VERSION 5.8 ;
BUSBITCHARS "[]" ;
DIVIDERCHAR "/" ;

UNITS
  DATABASE MICRONS 1000 ;
END UNITS

MANUFACTURINGGRID 0.005 ;

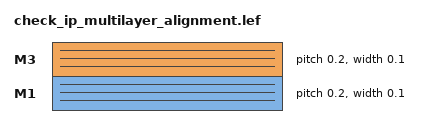
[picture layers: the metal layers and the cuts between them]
LAYER M1
  TYPE ROUTING ;
  DIRECTION HORIZONTAL ;
  PITCH 0.200 ;
  WIDTH 0.100 ;
END M1

LAYER M3
  TYPE ROUTING ;
  DIRECTION HORIZONTAL ;
  PITCH 0.200 ;
  WIDTH 0.100 ;
END M3

SITE unit
  CLASS CORE ;
  SIZE 0.200 BY 2.000 ;
  SYMMETRY Y ;
END unit

# M1 center_y=150: with track origin 100 it needs translation 150 mod 200.
# M3 center_y=50: with track origin 0 it also needs translation 150 mod 200.
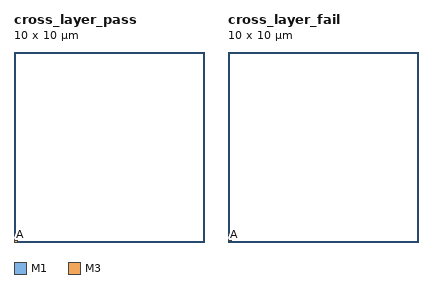
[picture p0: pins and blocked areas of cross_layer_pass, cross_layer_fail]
MACRO cross_layer_pass
  CLASS BLOCK ;
  ORIGIN 0 0 ;
  SIZE 10.000 BY 10.000 ;
  PIN A
    DIRECTION INPUT ;
    USE SIGNAL ;
    ANTENNAMODEL OXIDE1 ;
    PORT
      LAYER M1 ;
      RECT 0.000 0.100 0.200 0.200 ;
    END
  END A
  PIN B
    DIRECTION INPUT ;
    USE SIGNAL ;
    ANTENNAMODEL OXIDE1 ;
    PORT
      LAYER M3 ;
      RECT 0.000 0.000 0.200 0.100 ;
    END
  END B
END cross_layer_pass

# Both centers are 150. M1 needs translation 150 mod 200, while M3 needs
# translation 50 mod 200. Each layer can align alone, but not simultaneously.
MACRO cross_layer_fail
  CLASS BLOCK ;
  ORIGIN 0 0 ;
  SIZE 10.000 BY 10.000 ;
  PIN A
    DIRECTION INPUT ;
    USE SIGNAL ;
    ANTENNAMODEL OXIDE1 ;
    PORT
      LAYER M1 ;
      RECT 0.000 0.100 0.200 0.200 ;
    END
  END A
  PIN B
    DIRECTION INPUT ;
    USE SIGNAL ;
    ANTENNAMODEL OXIDE1 ;
    PORT
      LAYER M3 ;
      RECT 0.000 0.100 0.200 0.200 ;
    END
  END B
END cross_layer_fail

END LIBRARY
